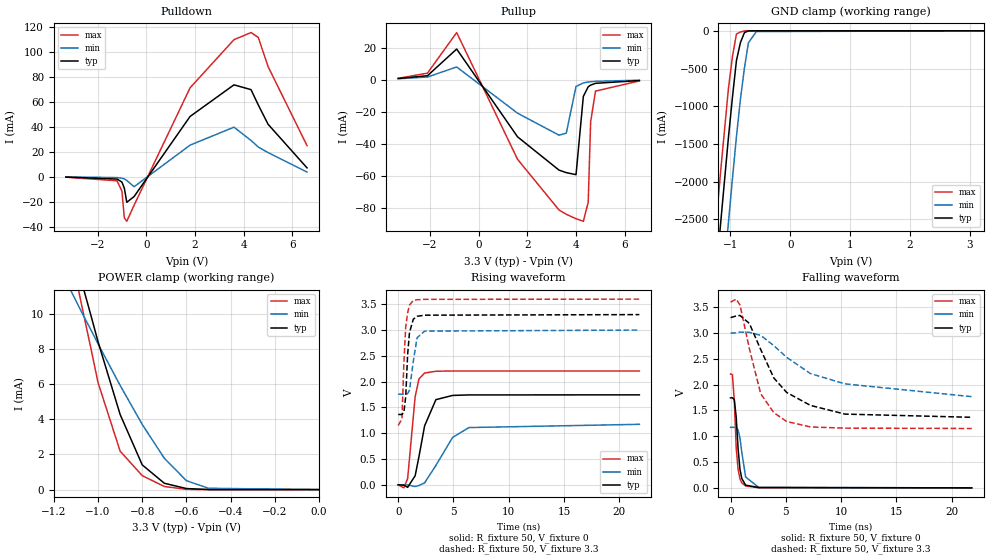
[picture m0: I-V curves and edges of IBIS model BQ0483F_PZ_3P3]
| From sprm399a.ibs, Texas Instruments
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|   Model Cell BQ0483F_PZ_3P3
|BQ0483F_PZ_3P3
[Model]   BQ0483F_PZ_3P3
Model_type   I/O
Polarity   Non-Inverting
Enable   Active-Low
Vinl =  1.15
Vinh =  1.65
Cref =  15.0001pF
Rref =  101.0000M
Vref =  0V
Vmeas =  1.65
C_comp   1.2p   1.2p   1.2p
[Model Spec]
Vinl   1.15   1.05   1.15
Vinh   1.65   1.65   1.65
[Temperature Range]   25   125   -40
[Voltage Range]   3.3   3   3.6
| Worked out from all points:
|   slope of the pulldown table from 0 to 0.495 V, typ, clamps not added: 32.6 ohm
|   slope of the pullup table from 0 to 0.495 V, typ, clamps not added: 41.1 ohm
|   GND clamp passes 1 mA (typ) near -0.67 V on its own axis
|   POWER clamp passes 1 mA (typ) near -0.76 V on its own axis
|   rising waveform, R_fixture 50, V_fixture 0: 20-80 % time 987ps typ, 1.96ns min, 560ps max; typ from 0 V to 1.74 V
|   rising waveform, R_fixture 50, V_fixture 3.3: 20-80 % time 316ps typ, 419ps min, 312ps max; typ from 1.36 V to 3.3 V
|   falling waveform, R_fixture 50, V_fixture 0: 20-80 % time 362ps typ, 474ps min, 334ps max; typ from 1.74 V to 0 V
|   falling waveform, R_fixture 50, V_fixture 3.3: 20-80 % time 3.44ns typ, 6.45ns min, 1.87ns max; typ from 3.3 V to 1.37 V
[POWER_clamp]
|   voltage   I(typ)   I(min)   I(max)
-3.3V     126.2mA    68.24mA    170.7mA
-1.133V   14.62mA    11.56mA    14.25mA
-1.1V     13.01mA    10.73mA    12.05mA
-1.067V   11.48mA    9.911mA    10.06mA
-1.033V   9.94mA     9.098mA    8.07mA
-1V       8.404mA    8.284mA    6.083mA
-900mV    4.269mA    5.922mA    2.185mA
-800mV    1.404mA    3.703mA    792.5uA
-700mV    359.8uA    1.779mA    177.2uA
-600mV    60.02uA    505.6uA    15.26uA
-500mV    5.174uA    75.93uA    589.6nA
0V        344.1pA    2.024nA    395.4pA
[Pulldown]
|   voltage   I(typ)   I(min)   I(max)
-3.3V     -235.3uA   -110.8uA   -321uA
-1.2V     -1.831mA   -650uA     -3.19mA
-1V       -4.234mA   -1.115mA   -11.41mA
-900mV    -9.124mA   -1.665mA   -32.86mA
-800mV    -20.38mA   -2.929mA   -35.56mA
-500mV    -15.78mA   -7.942mA   -22.73mA
1.8V      48.21mA    25.28mA    71.1mA
3.6V      73.43mA    39.64mA    109.5mA
4.3V      69.62mA    29.03mA    115.2mA
4.6V      57.33mA    23.76mA    111.3mA
5V        41.97mA    19.31mA    88.04mA
6.6V      7.109mA    3.772mA    24.87mA
[Pullup]
|   voltage   I(typ)   I(min)   I(max)
-3.3V     707uA      560.2uA    814uA
-2.1V     2.419mA    1.616mA    4.016mA
-900mV    19.05mA    7.888mA    29.32mA
1.6V      -35.65mA   -20.92mA   -49.67mA
3.3V      -56.37mA   -34.59mA   -81.2mA
3.6V      -57.96mA   -33.36mA   -83.9mA
4V        -59.21mA   -4.264mA   -86.68mA
4.3V      -10.46mA   -2.036mA   -88.27mA
4.5V      -4.473mA   -1.491mA   -76.44mA
4.6V      -3.426mA   -1.312mA   -26.26mA
4.8V      -2.312mA   -1.056mA   -7.153mA
6.6V      -565.6uA   -375.3uA   -812.8uA
[GND_clamp]
|   voltage   I(typ)   I(min)   I(max)
-3.3V     -23.34A    -24.42A    -22.71A
-1.3V     -3.808A    -4.968A    -3.114A
-1.233V   -3.19A     -4.349A    -2.495A
-1.167V   -2.579A    -3.735A    -1.888A
-1.033V   -1.408A    -2.537A    -758.4mA
-966.7mV  -880.9mA   -1.962A    -341.4mA
-900mV    -395.3mA   -1.403A    -41.5mA
-833.3mV  -155.8mA   -909mA     -15.63mA
-766.7mV  -24.48mA   -494mA     -1.884mA
-700mV    -1.341mA   -158.2mA   -251.5uA
-566.7mV  -36.4uA    -9.842mA   -9.579uA
3.233V    330.4pA    260.4nA    312.9pA
[Ramp]
| variable   typ   min   max
dV/dt_f   1.588113/5.856848n   1.020005/10.8857n   2.008308/3.200862n
dV/dt_r   1.434081/1.566014n   0.965318/3.102651n   1.812972/0.8778339n
R_load = 50
[Rising Waveform]
R_fixture = 50
V_fixture = 0
V_fixture_min = 0
V_fixture_max = 0
|   time   V(typ)   V(min)   V(max)
0s        -27.79uV   -38.14uV   73.74uV
512ps     -5.626mV   237.6uV    -58.83mV
852ps     -48.32mV   -2.152mV   121mV
1.532ns   175.8mV    -32.48mV   1.708V
1.876ns   546.1mV    -13.37mV   2.053V
2.388ns   1.144V     38.02mV    2.167V
3.408ns   1.651V     376.5mV    2.202V
4.916ns   1.733V     918.2mV    2.207V
6.4ns     1.743V     1.11V      2.207V
21.81ns   1.744V     1.173V     2.207V
[Rising Waveform]
R_fixture = 50
V_fixture = 3.3
V_fixture_min = 3
V_fixture_max = 3.6
|   time   V(typ)   V(min)   V(max)
0s        1.365V     1.758V     1.151V
340ps     1.362V     1.757V     1.279V
512ps     1.404V     1.755V     2.37V
680ps     1.713V     1.755V     3.064V
852ps     2.525V     1.77V      3.335V
1.02ns    2.954V     1.836V     3.486V
1.364ns   3.21V      2.394V     3.576V
1.704ns   3.267V     2.851V     3.588V
2.388ns   3.289V     2.98V      3.596V
21.81ns   3.3V       3V         3.6V
[Falling Waveform]
R_fixture = 50
V_fixture = 0
V_fixture_min = 0
V_fixture_max = 0
|   time   V(typ)   V(min)   V(max)
0s        1.744V     1.173V     2.207V
168ps     1.747V     1.173V     2.195V
340ps     1.708V     1.175V     1.688V
512ps     1.371V     1.167V     773.8mV
680ps     764.3mV    1.123V     360.6mV
852ps     358.5mV    966.1mV    176.4mV
1.02ns    179mV      685.7mV    96.8mV
1.364ns   52.45mV    210.6mV    35.5mV
2.556ns   6.702mV    8.261mV    2.908mV
21.81ns   10.03uV    49.38uV    1.638uV
[Falling Waveform]
R_fixture = 50
V_fixture = 3.3
V_fixture_min = 3
V_fixture_max = 3.6
|   time   V(typ)   V(min)   V(max)
0s        3.3V       3V         3.599V
512ps     3.333V     3.005V     3.659V
852ps     3.343V     3.02V      3.546V
1.704ns   3.187V     3.015V     2.698V
2.728ns   2.681V     2.956V     1.824V
3.92ns    2.129V     2.756V     1.456V
5.08ns    1.849V     2.53V      1.286V
7.224ns   1.599V     2.216V     1.181V
10.34ns   1.43V      2.016V     1.158V
21.81ns   1.368V     1.768V     1.151V
